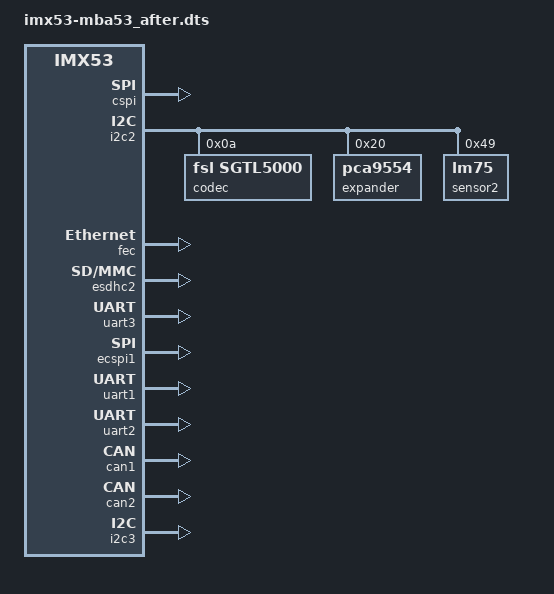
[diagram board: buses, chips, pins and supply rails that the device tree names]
		pinctrl_disp1_1: disp1-grp1 {
			fsl,pins = <689 0x10000		/* DISP1_DRDY	*/
				    482 0x10000		/* DISP1_HSYNC	*/
				    489 0x10000		/* DISP1_VSYNC	*/
				    515 0x10000		/* DISP1_DAT_22	*/
				    523 0x10000		/* DISP1_DAT_23	*/
				    545 0x10000		/* DISP1_DAT_21	*/
				    553 0x10000		/* DISP1_DAT_20	*/
				    558 0x10000		/* DISP1_DAT_19	*/
				    564 0x10000		/* DISP1_DAT_18	*/
				    570 0x10000		/* DISP1_DAT_17	*/
				    575 0x10000		/* DISP1_DAT_16	*/
				    580 0x10000		/* DISP1_DAT_15	*/
				    585 0x10000		/* DISP1_DAT_14	*/
				    590 0x10000		/* DISP1_DAT_13	*/
				    595 0x10000		/* DISP1_DAT_12	*/
				    628 0x10000		/* DISP1_DAT_11	*/
				    634 0x10000		/* DISP1_DAT_10	*/
				    639 0x10000		/* DISP1_DAT_9	*/
				    644 0x10000		/* DISP1_DAT_8	*/
				    649 0x10000		/* DISP1_DAT_7	*/
				    654 0x10000		/* DISP1_DAT_6	*/
				    659 0x10000		/* DISP1_DAT_5	*/
				    664 0x10000		/* DISP1_DAT_4	*/
				    669 0x10000		/* DISP1_DAT_3	*/
				    674 0x10000		/* DISP1_DAT_2	*/
				    679 0x10000		/* DISP1_DAT_1	*/
				    684 0x10000>;	/* DISP1_DAT_0	*/
		};
	};
};

&cspi {
	status = "okay";
};

&i2c2 {
	codec: sgtl5000@a {
		compatible = "fsl,sgtl5000";
		reg = <0x0a>;
	};

	expander: pca9554@20 {
		compatible = "pca9554";
		reg = <0x20>;
		interrupts = <109>;
	};

	sensor2: lm75@49 {
		compatible = "lm75";
		reg = <0x49>;
	};
};

&fec {
	status = "okay";
};

&esdhc2 {
	status = "okay";
};

&uart3 {
	status = "okay";
};

&ecspi1 {
	status = "okay";
};

&uart1 {
	status = "okay";
};

&uart2 {
	status = "okay";
};

&can1 {
	status = "okay";
};

&can2 {
	status = "okay";
};

&i2c3 {
	status = "okay";
};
